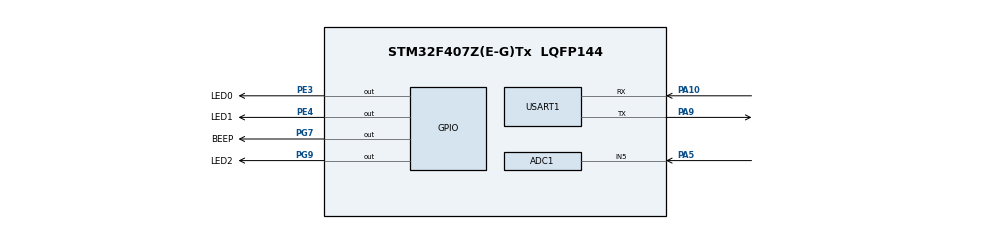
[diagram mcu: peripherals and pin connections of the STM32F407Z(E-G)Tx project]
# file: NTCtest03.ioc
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ADC1.Channel-0\#ChannelRegularConversion=ADC_CHANNEL_5
ADC1.NbrOfConversionFlag=1
ADC1.Rank-0\#ChannelRegularConversion=1
ADC1.SamplingTime-0\#ChannelRegularConversion=ADC_SAMPLETIME_3CYCLES
ADC1.master=1
Mcu.Family=STM32F4
Mcu.Name=STM32F407Z(E-G)Tx
Mcu.Package=LQFP144
NVIC.ADC_IRQn=true\:0\:0\:false\:false\:true\:true\:true
NVIC.PriorityGroup=NVIC_PRIORITYGROUP_4
NVIC.USART1_IRQn=true\:0\:0\:false\:false\:true\:true\:true
PA10.Mode=Asynchronous
PA10.Signal=USART1_RX
PA5.Signal=ADCx_IN5
PA9.Mode=Asynchronous
PA9.Signal=USART1_TX
PE3.GPIO_Label=LED0
PE3.PinState=GPIO_PIN_SET
PE3.Signal=GPIO_Output
PE4.GPIO_Label=LED1
PE4.PinState=GPIO_PIN_SET
PE4.Signal=GPIO_Output
PG7.GPIO_Label=BEEP
PG7.Signal=GPIO_Output
PG9.GPIO_Label=LED2
PG9.PinState=GPIO_PIN_SET
PG9.Signal=GPIO_Output
PH0-OSC_IN.Mode=HSE-External-Oscillator
PH0-OSC_IN.Signal=RCC_OSC_IN
PH1-OSC_OUT.Mode=HSE-External-Oscillator
PH1-OSC_OUT.Signal=RCC_OSC_OUT
ProjectManager.HeapSize=0x200
ProjectManager.StackSize=0x400
ProjectManager.TargetToolchain=MDK-ARM V5.27
RCC.48MHZClocksFreq_Value=32000000
RCC.AHBCLKDivider=RCC_SYSCLK_DIV4
RCC.AHBFreq_Value=16000000
RCC.APB1Freq_Value=16000000
RCC.APB1TimFreq_Value=16000000
RCC.APB2Freq_Value=16000000
RCC.APB2TimFreq_Value=16000000
RCC.CortexFreq_Value=16000000
RCC.HCLKFreq_Value=16000000
RCC.HSE_VALUE=8000000
RCC.HSI_VALUE=16000000
RCC.LSE_VALUE=32768
RCC.PLLM=4
RCC.PLLN=64
RCC.PLLSourceVirtual=RCC_PLLSOURCE_HSE
RCC.SYSCLKFreq_VALUE=64000000
RCC.SYSCLKSource=RCC_SYSCLKSOURCE_PLLCLK
RCC.VCOOutputFreq_Value=128000000
SH.ADCx_IN5.0=ADC1_IN5,IN5
USART1.VirtualMode=VM_ASYNC
board=custom

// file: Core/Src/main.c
/* USER CODE BEGIN Header */
/**
  ******************************************************************************
  * @file           : main.c
  * @brief          : Main program body
  ******************************************************************************
  * @attention
  *
  * <h2><center>&copy; Copyright (c) 2021 STMicroelectronics.
  * All rights reserved.</center></h2>
  *
  * This software component is licensed by ST under BSD 3-Clause license,
  * the "License"; You may not use this file except in compliance with the
  * License. You may obtain a copy of the License at:
  *                        opensource.org/licenses/BSD-3-Clause
  *
  ******************************************************************************
  */
/* USER CODE END Header */
#include "main.h"
#include "adc.h"
#include "usart.h"
#include "gpio.h"

/* USER CODE BEGIN Includes */
#include "NTC.h"
/* USER CODE END Includes */

void SystemClock_Config(void);

int main(void)
{

  /* MCU Configuration--------------------------------------------------------*/

  /* Reset of all peripherals, Initializes the Flash interface and the Systick. */
  HAL_Init();

  /* Configure the system clock */
  SystemClock_Config();

  /* Initialize all configured peripherals */
  MX_GPIO_Init();
  MX_ADC1_Init();
  MX_USART1_UART_Init();

  /* Infinite loop */
  /* USER CODE BEGIN WHILE */
  while (1)
  {
		HAL_GPIO_TogglePin(LED1_GPIO_Port,LED1_Pin);
		HAL_Delay(2000);
		printf("当前温度为：%d ℃\r\n",	Get_Temp(&hadc1));
		printf("(高精度版本)当前温度为：%.2lf ℃\r\n",Get_Temp_Precise(&hadc1));
		printf("(高精度PJL版本)当前温度为：%.2lf ℃\r\n",Get_Temp_PJL(&hadc1));
    /* USER CODE END WHILE */

  }
}

void SystemClock_Config(void)
{
  RCC_OscInitTypeDef RCC_OscInitStruct = {0};
  RCC_ClkInitTypeDef RCC_ClkInitStruct = {0};

  /** Configure the main internal regulator output voltage
  */
  __HAL_RCC_PWR_CLK_ENABLE();
  __HAL_PWR_VOLTAGESCALING_CONFIG(PWR_REGULATOR_VOLTAGE_SCALE1);
  /** Initializes the RCC Oscillators according to the specified parameters
  * in the RCC_OscInitTypeDef structure.
  */
  RCC_OscInitStruct.OscillatorType = RCC_OSCILLATORTYPE_HSE;
  RCC_OscInitStruct.HSEState = RCC_HSE_ON;
  RCC_OscInitStruct.PLL.PLLState = RCC_PLL_ON;
  RCC_OscInitStruct.PLL.PLLSource = RCC_PLLSOURCE_HSE;
  RCC_OscInitStruct.PLL.PLLM = 4;
  RCC_OscInitStruct.PLL.PLLN = 64;
  RCC_OscInitStruct.PLL.PLLP = RCC_PLLP_DIV2;
  RCC_OscInitStruct.PLL.PLLQ = 4;
  if (HAL_RCC_OscConfig(&RCC_OscInitStruct) != HAL_OK)
  {
    Error_Handler();
  }
  /** Initializes the CPU, AHB and APB buses clocks
  */
  RCC_ClkInitStruct.ClockType = RCC_CLOCKTYPE_HCLK|RCC_CLOCKTYPE_SYSCLK
                              |RCC_CLOCKTYPE_PCLK1|RCC_CLOCKTYPE_PCLK2;
  RCC_ClkInitStruct.SYSCLKSource = RCC_SYSCLKSOURCE_PLLCLK;
  RCC_ClkInitStruct.AHBCLKDivider = RCC_SYSCLK_DIV8;
  RCC_ClkInitStruct.APB1CLKDivider = RCC_HCLK_DIV1;
  RCC_ClkInitStruct.APB2CLKDivider = RCC_HCLK_DIV1;

  if (HAL_RCC_ClockConfig(&RCC_ClkInitStruct, FLASH_LATENCY_0) != HAL_OK)
  {
    Error_Handler();
  }
}

void Error_Handler(void)
{
  __disable_irq();
  while (1)
  {
  }
}

/************************ (C) COPYRIGHT STMicroelectronics *****END OF FILE****/
